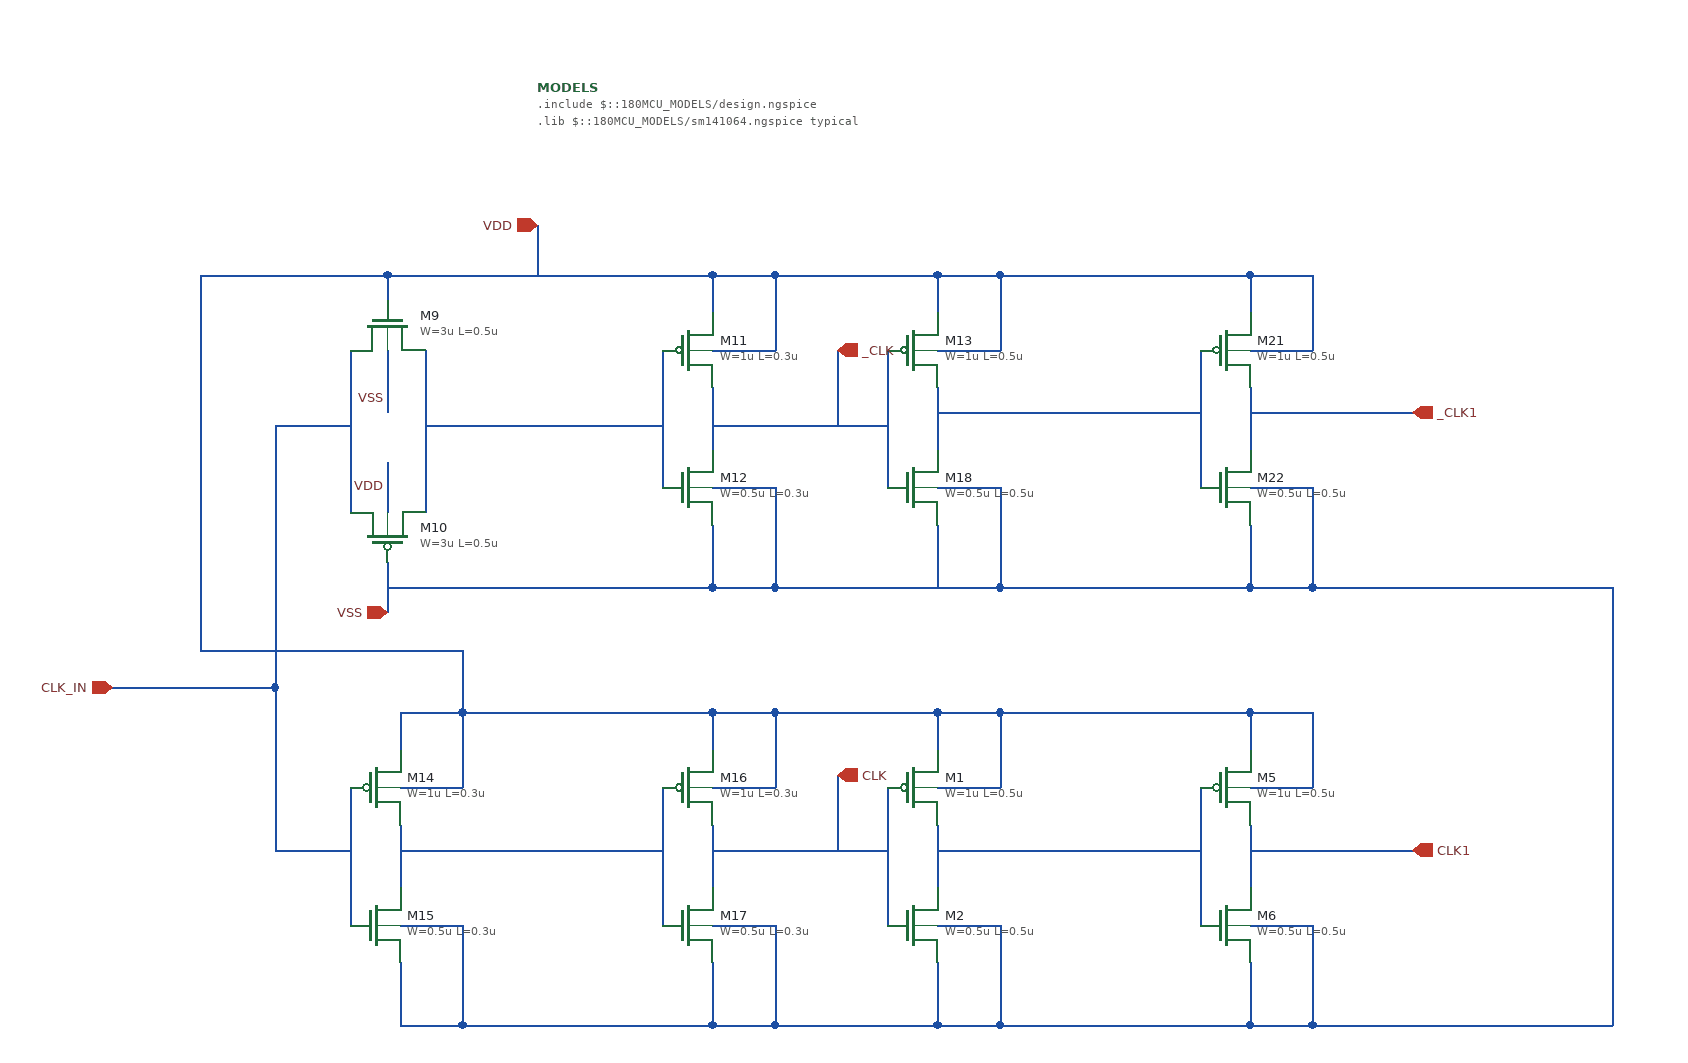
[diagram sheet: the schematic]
v {xschem version=3.4.7 file_version=1.2}
G {}
K {}
V {}
S {}
E {}
N 310 270 310 400 {lab=CLK_IN}
N 370 270 370 400 {lab=#net1}
N 340 270 340 320 {lab=VSS}
N 340 360 340 400 {lab=VDD}
N 340 440 340 480 {lab=VSS}
N 180 540 250 540 {lab=CLK_IN}
N 250 330 250 540 {lab=CLK_IN}
N 250 330 310 330 {lab=CLK_IN}
N 560 270 560 380 {lab=#net1}
N 370 330 560 330 {lab=#net1}
N 600 300 600 360 {lab=_CLK}
N 600 330 740 330 {lab=_CLK}
N 340 210 400 210 {lab=VDD}
N 400 210 600 210 {lab=VDD}
N 600 210 600 240 {lab=VDD}
N 340 460 600 460 {lab=VSS}
N 600 410 600 460 {lab=VSS}
N 600 270 650 270 {lab=VDD}
N 650 210 650 270 {lab=VDD}
N 600 210 650 210 {lab=VDD}
N 600 380 650 380 {lab=VSS}
N 650 380 650 460 {lab=VSS}
N 600 460 640 460 {lab=VSS}
N 640 460 650 460 {lab=VSS}
N 310 620 310 730 {lab=CLK_IN}
N 350 650 350 710 {lab=#net2}
N 350 560 350 590 {lab=VDD}
N 350 760 350 810 {lab=VSS}
N 350 620 400 620 {lab=VDD}
N 400 560 400 620 {lab=VDD}
N 350 560 400 560 {lab=VDD}
N 350 730 400 730 {lab=VSS}
N 400 730 400 810 {lab=VSS}
N 350 810 390 810 {lab=VSS}
N 390 810 400 810 {lab=VSS}
N 250 540 250 670 {lab=CLK_IN}
N 250 670 310 670 {lab=CLK_IN}
N 560 620 560 730 {lab=#net2}
N 600 650 600 710 {lab=CLK1}
N 600 560 600 590 {lab=VDD}
N 600 760 600 810 {lab=VSS}
N 600 620 650 620 {lab=VDD}
N 650 560 650 620 {lab=VDD}
N 600 560 650 560 {lab=VDD}
N 600 730 650 730 {lab=VSS}
N 650 730 650 810 {lab=VSS}
N 600 810 640 810 {lab=VSS}
N 640 810 650 810 {lab=VSS}
N 350 670 560 670 {lab=#net2}
N 600 670 740 670 {lab=CLK1}
N 400 560 600 560 {lab=VDD}
N 400 810 600 810 {lab=VSS}
N 400 510 400 560 {lab=VDD}
N 200 510 400 510 {lab=VDD}
N 740 620 740 730 {lab=CLK1}
N 780 650 780 710 {lab=#net3}
N 780 560 780 590 {lab=VDD}
N 780 760 780 810 {lab=VSS}
N 780 620 830 620 {lab=VDD}
N 830 560 830 620 {lab=VDD}
N 780 560 830 560 {lab=VDD}
N 780 730 830 730 {lab=VSS}
N 830 730 830 810 {lab=VSS}
N 780 810 820 810 {lab=VSS}
N 820 810 830 810 {lab=VSS}
N 990 620 990 730 {lab=#net3}
N 1030 650 1030 710 {lab=CLK1}
N 1030 560 1030 590 {lab=VDD}
N 1030 760 1030 810 {lab=VSS}
N 1030 620 1080 620 {lab=VDD}
N 1080 560 1080 620 {lab=VDD}
N 1030 560 1080 560 {lab=VDD}
N 1030 730 1080 730 {lab=VSS}
N 1080 730 1080 810 {lab=VSS}
N 1030 810 1070 810 {lab=VSS}
N 1070 810 1080 810 {lab=VSS}
N 780 670 990 670 {lab=#net3}
N 830 560 1030 560 {lab=VDD}
N 830 810 1030 810 {lab=VSS}
N 1030 670 1160 670 {lab=CLK1}
N 740 270 740 380 {lab=_CLK}
N 780 300 780 360 {lab=#net4}
N 780 210 780 240 {lab=VDD}
N 780 410 780 460 {lab=VSS}
N 780 270 830 270 {lab=VDD}
N 830 210 830 270 {lab=VDD}
N 780 210 830 210 {lab=VDD}
N 780 380 830 380 {lab=VSS}
N 830 380 830 460 {lab=VSS}
N 780 460 820 460 {lab=VSS}
N 820 460 830 460 {lab=VSS}
N 990 270 990 380 {lab=#net4}
N 1030 300 1030 360 {lab=_CLK1}
N 1030 210 1030 240 {lab=VDD}
N 1030 410 1030 460 {lab=VSS}
N 1030 270 1080 270 {lab=VDD}
N 1080 210 1080 270 {lab=VDD}
N 1030 210 1080 210 {lab=VDD}
N 1030 380 1080 380 {lab=VSS}
N 1080 380 1080 460 {lab=VSS}
N 1030 460 1070 460 {lab=VSS}
N 1070 460 1080 460 {lab=VSS}
N 780 320 990 320 {lab=#net4}
N 830 210 1030 210 {lab=VDD}
N 830 460 1030 460 {lab=VSS}
N 1030 320 1160 320 {lab=_CLK1}
N 650 210 780 210 {lab=VDD}
N 650 460 790 460 {lab=VSS}
N 650 560 780 560 {lab=VDD}
N 650 810 780 810 {lab=VSS}
N 120 540 180 540 {lab=CLK_IN}
N 340 210 340 230 {lab=VDD}
N 190 210 340 210 {lab=VDD}
N 190 210 190 510 {lab=VDD}
N 190 510 200 510 {lab=VDD}
N 460 170 460 210 {lab=VDD}
N 1080 460 1320 460 {lab=VSS}
N 1320 460 1320 810 {lab=VSS}
N 1080 810 1320 810 {lab=VSS}
N 700 270 700 330 {lab=_CLK}
N 700 610 700 670 {lab=CLK1}
C {symbols/nfet_03v3.sym} 340 250 1 0 {name=M9
L=0.5u
W=3u
nf=5
m=1
ad="'int((nf+1)/2) * W/nf * 0.18u'"
pd="'2*int((nf+1)/2) * (W/nf + 0.18u)'"
as="'int((nf+2)/2) * W/nf * 0.18u'"
ps="'2*int((nf+2)/2) * (W/nf + 0.18u)'"
nrd="'0.18u / W'" nrs="'0.18u / W'"
sa=0 sb=0 sd=0
model=nfet_03v3
spiceprefix=X
}
C {symbols/pfet_03v3.sym} 340 420 1 1 {name=M10
L=0.5u
W=3u
nf=5
m=1
ad="'int((nf+1)/2) * W/nf * 0.18u'"
pd="'2*int((nf+1)/2) * (W/nf + 0.18u)'"
as="'int((nf+2)/2) * W/nf * 0.18u'"
ps="'2*int((nf+2)/2) * (W/nf + 0.18u)'"
nrd="'0.18u / W'" nrs="'0.18u / W'"
sa=0 sb=0 sd=0
model=pfet_03v3
spiceprefix=X
}
C {lab_wire.sym} 340 310 0 0 {name=p20 sig_type=std_logic lab=VSS}
C {lab_wire.sym} 340 380 0 0 {name=p21 sig_type=std_logic lab=VDD}
C {symbols/pfet_03v3.sym} 580 270 0 0 {name=M11
L=0.3u
W=1u
nf=1
m=1
ad="'int((nf+1)/2) * W/nf * 0.18u'"
pd="'2*int((nf+1)/2) * (W/nf + 0.18u)'"
as="'int((nf+2)/2) * W/nf * 0.18u'"
ps="'2*int((nf+2)/2) * (W/nf + 0.18u)'"
nrd="'0.18u / W'" nrs="'0.18u / W'"
sa=0 sb=0 sd=0
model=pfet_03v3
spiceprefix=X
}
C {symbols/nfet_03v3.sym} 580 380 0 0 {name=M12
L=0.3u
W=0.5u
nf=1
m=1
ad="'int((nf+1)/2) * W/nf * 0.18u'"
pd="'2*int((nf+1)/2) * (W/nf + 0.18u)'"
as="'int((nf+2)/2) * W/nf * 0.18u'"
ps="'2*int((nf+2)/2) * (W/nf + 0.18u)'"
nrd="'0.18u / W'" nrs="'0.18u / W'"
sa=0 sb=0 sd=0
model=nfet_03v3
spiceprefix=X
}
C {opin.sym} 1160 320 0 0 {name=p25 sig_type=std_logic lab=_CLK1}
C {symbols/pfet_03v3.sym} 330 620 0 0 {name=M14
L=0.3u
W=1u
nf=1
m=1
ad="'int((nf+1)/2) * W/nf * 0.18u'"
pd="'2*int((nf+1)/2) * (W/nf + 0.18u)'"
as="'int((nf+2)/2) * W/nf * 0.18u'"
ps="'2*int((nf+2)/2) * (W/nf + 0.18u)'"
nrd="'0.18u / W'" nrs="'0.18u / W'"
sa=0 sb=0 sd=0
model=pfet_03v3
spiceprefix=X
}
C {symbols/nfet_03v3.sym} 330 730 0 0 {name=M15
L=0.3u
W=0.5u
nf=1
m=1
ad="'int((nf+1)/2) * W/nf * 0.18u'"
pd="'2*int((nf+1)/2) * (W/nf + 0.18u)'"
as="'int((nf+2)/2) * W/nf * 0.18u'"
ps="'2*int((nf+2)/2) * (W/nf + 0.18u)'"
nrd="'0.18u / W'" nrs="'0.18u / W'"
sa=0 sb=0 sd=0
model=nfet_03v3
spiceprefix=X
}
C {symbols/pfet_03v3.sym} 580 620 0 0 {name=M16
L=0.3u
W=1u
nf=1
m=1
ad="'int((nf+1)/2) * W/nf * 0.18u'"
pd="'2*int((nf+1)/2) * (W/nf + 0.18u)'"
as="'int((nf+2)/2) * W/nf * 0.18u'"
ps="'2*int((nf+2)/2) * (W/nf + 0.18u)'"
nrd="'0.18u / W'" nrs="'0.18u / W'"
sa=0 sb=0 sd=0
model=pfet_03v3
spiceprefix=X
}
C {symbols/nfet_03v3.sym} 580 730 0 0 {name=M17
L=0.3u
W=0.5u
nf=1
m=1
ad="'int((nf+1)/2) * W/nf * 0.18u'"
pd="'2*int((nf+1)/2) * (W/nf + 0.18u)'"
as="'int((nf+2)/2) * W/nf * 0.18u'"
ps="'2*int((nf+2)/2) * (W/nf + 0.18u)'"
nrd="'0.18u / W'" nrs="'0.18u / W'"
sa=0 sb=0 sd=0
model=nfet_03v3
spiceprefix=X
}
C {ipin.sym} 120 540 0 0 {name=p23 sig_type=std_logic lab=CLK_IN}
C {noconn.sym} 740 330 2 0 {name=l3}
C {noconn.sym} 740 670 2 0 {name=l4}
C {symbols/pfet_03v3.sym} 760 620 0 0 {name=M1
L=0.5u
W=1u
nf=2
m=1
ad="'int((nf+1)/2) * W/nf * 0.18u'"
pd="'2*int((nf+1)/2) * (W/nf + 0.18u)'"
as="'int((nf+2)/2) * W/nf * 0.18u'"
ps="'2*int((nf+2)/2) * (W/nf + 0.18u)'"
nrd="'0.18u / W'" nrs="'0.18u / W'"
sa=0 sb=0 sd=0
model=pfet_03v3
spiceprefix=X
}
C {symbols/nfet_03v3.sym} 760 730 0 0 {name=M2
L=0.5u
W=0.5u
nf=1
m=1
ad="'int((nf+1)/2) * W/nf * 0.18u'"
pd="'2*int((nf+1)/2) * (W/nf + 0.18u)'"
as="'int((nf+2)/2) * W/nf * 0.18u'"
ps="'2*int((nf+2)/2) * (W/nf + 0.18u)'"
nrd="'0.18u / W'" nrs="'0.18u / W'"
sa=0 sb=0 sd=0
model=nfet_03v3
spiceprefix=X
}
C {symbols/pfet_03v3.sym} 1010 620 0 0 {name=M5
L=0.5u
W=1u
nf=2
m=1
ad="'int((nf+1)/2) * W/nf * 0.18u'"
pd="'2*int((nf+1)/2) * (W/nf + 0.18u)'"
as="'int((nf+2)/2) * W/nf * 0.18u'"
ps="'2*int((nf+2)/2) * (W/nf + 0.18u)'"
nrd="'0.18u / W'" nrs="'0.18u / W'"
sa=0 sb=0 sd=0
model=pfet_03v3
spiceprefix=X
}
C {symbols/nfet_03v3.sym} 1010 730 0 0 {name=M6
L=0.5u
W=0.5u
nf=1
m=1
ad="'int((nf+1)/2) * W/nf * 0.18u'"
pd="'2*int((nf+1)/2) * (W/nf + 0.18u)'"
as="'int((nf+2)/2) * W/nf * 0.18u'"
ps="'2*int((nf+2)/2) * (W/nf + 0.18u)'"
nrd="'0.18u / W'" nrs="'0.18u / W'"
sa=0 sb=0 sd=0
model=nfet_03v3
spiceprefix=X
}
C {opin.sym} 1160 670 0 0 {name=p2 sig_type=std_logic lab=CLK1}
C {noconn.sym} 740 320 2 0 {name=l5}
C {symbols/pfet_03v3.sym} 760 270 0 0 {name=M13
L=0.5u
W=1u
nf=2
m=1
ad="'int((nf+1)/2) * W/nf * 0.18u'"
pd="'2*int((nf+1)/2) * (W/nf + 0.18u)'"
as="'int((nf+2)/2) * W/nf * 0.18u'"
ps="'2*int((nf+2)/2) * (W/nf + 0.18u)'"
nrd="'0.18u / W'" nrs="'0.18u / W'"
sa=0 sb=0 sd=0
model=pfet_03v3
spiceprefix=X
}
C {symbols/nfet_03v3.sym} 760 380 0 0 {name=M18
L=0.5u
W=0.5u
nf=1
m=1
ad="'int((nf+1)/2) * W/nf * 0.18u'"
pd="'2*int((nf+1)/2) * (W/nf + 0.18u)'"
as="'int((nf+2)/2) * W/nf * 0.18u'"
ps="'2*int((nf+2)/2) * (W/nf + 0.18u)'"
nrd="'0.18u / W'" nrs="'0.18u / W'"
sa=0 sb=0 sd=0
model=nfet_03v3
spiceprefix=X
}
C {symbols/pfet_03v3.sym} 1010 270 0 0 {name=M21
L=0.5u
W=1u
nf=2
m=1
ad="'int((nf+1)/2) * W/nf * 0.18u'"
pd="'2*int((nf+1)/2) * (W/nf + 0.18u)'"
as="'int((nf+2)/2) * W/nf * 0.18u'"
ps="'2*int((nf+2)/2) * (W/nf + 0.18u)'"
nrd="'0.18u / W'" nrs="'0.18u / W'"
sa=0 sb=0 sd=0
model=pfet_03v3
spiceprefix=X
}
C {symbols/nfet_03v3.sym} 1010 380 0 0 {name=M22
L=0.5u
W=0.5u
nf=1
m=1
ad="'int((nf+1)/2) * W/nf * 0.18u'"
pd="'2*int((nf+1)/2) * (W/nf + 0.18u)'"
as="'int((nf+2)/2) * W/nf * 0.18u'"
ps="'2*int((nf+2)/2) * (W/nf + 0.18u)'"
nrd="'0.18u / W'" nrs="'0.18u / W'"
sa=0 sb=0 sd=0
model=nfet_03v3
spiceprefix=X
}
C {ipin.sym} 460 170 0 0 {name=p1 lab=VDD}
C {ipin.sym} 340 480 0 0 {name=p4 lab=VSS}
C {opin.sym} 700 270 3 0 {name=p3 sig_type=std_logic lab=_CLK}
C {opin.sym} 700 610 3 0 {name=p5 sig_type=std_logic lab=CLK}
C {devices/code_shown.sym} 460 60 0 0 {name=MODELS only_toplevel=true
format="tcleval( @value )"
value="
.include $::180MCU_MODELS/design.ngspice
.lib $::180MCU_MODELS/sm141064.ngspice typical
"}
